VERSION 5.7 ;
BUSBITCHARS "[]" ;
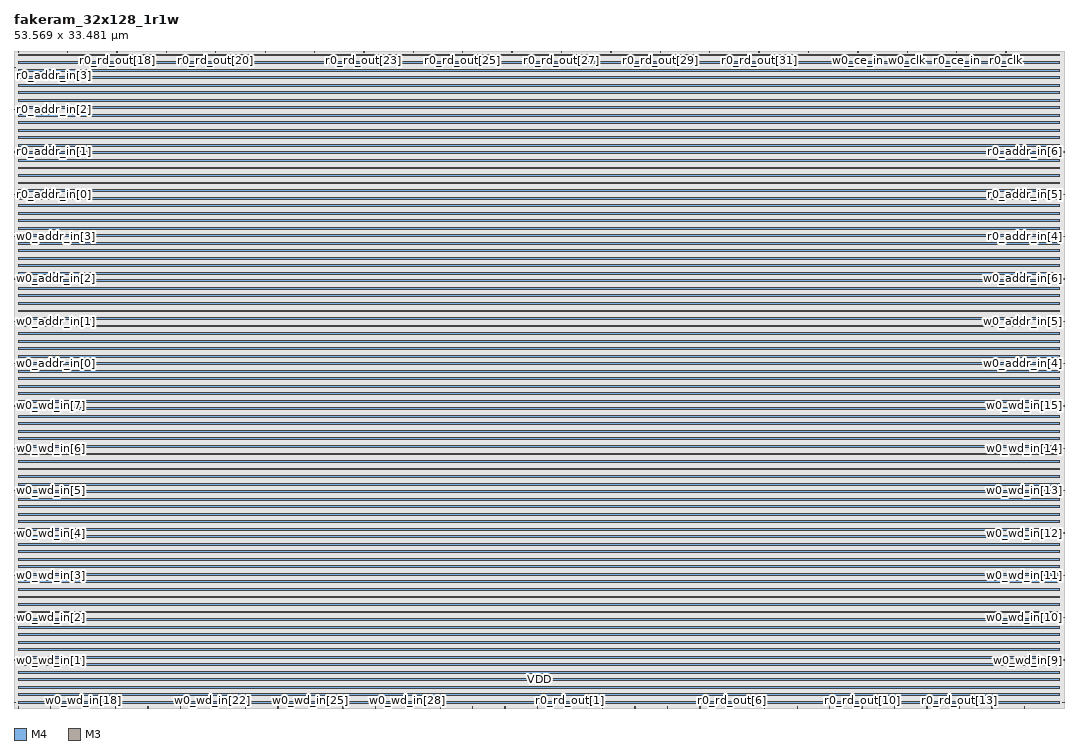
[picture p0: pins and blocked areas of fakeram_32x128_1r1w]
MACRO fakeram_32x128_1r1w
  FOREIGN fakeram_32x128_1r1w 0 0 ;
  SYMMETRY X Y R90 ;
  SIZE 53.569 BY 33.481 ;
  CLASS BLOCK ;
  PIN w0_wd_in[0]
    DIRECTION INPUT ;
    USE SIGNAL ;
    SHAPE ABUTMENT ;
    PORT
      LAYER M4 ;
      RECT 0.000 0.276 0.072 0.300 ;
    END
  END w0_wd_in[0]
  PIN w0_wd_in[1]
    DIRECTION INPUT ;
    USE SIGNAL ;
    SHAPE ABUTMENT ;
    PORT
      LAYER M4 ;
      RECT 0.000 2.436 0.072 2.460 ;
    END
  END w0_wd_in[1]
  PIN w0_wd_in[2]
    DIRECTION INPUT ;
    USE SIGNAL ;
    SHAPE ABUTMENT ;
    PORT
      LAYER M4 ;
      RECT 0.000 4.596 0.072 4.620 ;
    END
  END w0_wd_in[2]
  PIN w0_wd_in[3]
    DIRECTION INPUT ;
    USE SIGNAL ;
    SHAPE ABUTMENT ;
    PORT
      LAYER M4 ;
      RECT 0.000 6.756 0.072 6.780 ;
    END
  END w0_wd_in[3]
  PIN w0_wd_in[4]
    DIRECTION INPUT ;
    USE SIGNAL ;
    SHAPE ABUTMENT ;
    PORT
      LAYER M4 ;
      RECT 0.000 8.916 0.072 8.940 ;
    END
  END w0_wd_in[4]
  PIN w0_wd_in[5]
    DIRECTION INPUT ;
    USE SIGNAL ;
    SHAPE ABUTMENT ;
    PORT
      LAYER M4 ;
      RECT 0.000 11.076 0.072 11.100 ;
    END
  END w0_wd_in[5]
  PIN w0_wd_in[6]
    DIRECTION INPUT ;
    USE SIGNAL ;
    SHAPE ABUTMENT ;
    PORT
      LAYER M4 ;
      RECT 0.000 13.236 0.072 13.260 ;
    END
  END w0_wd_in[6]
  PIN w0_wd_in[7]
    DIRECTION INPUT ;
    USE SIGNAL ;
    SHAPE ABUTMENT ;
    PORT
      LAYER M4 ;
      RECT 0.000 15.396 0.072 15.420 ;
    END
  END w0_wd_in[7]
  PIN w0_wd_in[8]
    DIRECTION INPUT ;
    USE SIGNAL ;
    SHAPE ABUTMENT ;
    PORT
      LAYER M4 ;
      RECT 53.497 0.276 53.569 0.300 ;
    END
  END w0_wd_in[8]
  PIN w0_wd_in[9]
    DIRECTION INPUT ;
    USE SIGNAL ;
    SHAPE ABUTMENT ;
    PORT
      LAYER M4 ;
      RECT 53.497 2.436 53.569 2.460 ;
    END
  END w0_wd_in[9]
  PIN w0_wd_in[10]
    DIRECTION INPUT ;
    USE SIGNAL ;
    SHAPE ABUTMENT ;
    PORT
      LAYER M4 ;
      RECT 53.497 4.596 53.569 4.620 ;
    END
  END w0_wd_in[10]
  PIN w0_wd_in[11]
    DIRECTION INPUT ;
    USE SIGNAL ;
    SHAPE ABUTMENT ;
    PORT
      LAYER M4 ;
      RECT 53.497 6.756 53.569 6.780 ;
    END
  END w0_wd_in[11]
  PIN w0_wd_in[12]
    DIRECTION INPUT ;
    USE SIGNAL ;
    SHAPE ABUTMENT ;
    PORT
      LAYER M4 ;
      RECT 53.497 8.916 53.569 8.940 ;
    END
  END w0_wd_in[12]
  PIN w0_wd_in[13]
    DIRECTION INPUT ;
    USE SIGNAL ;
    SHAPE ABUTMENT ;
    PORT
      LAYER M4 ;
      RECT 53.497 11.076 53.569 11.100 ;
    END
  END w0_wd_in[13]
  PIN w0_wd_in[14]
    DIRECTION INPUT ;
    USE SIGNAL ;
    SHAPE ABUTMENT ;
    PORT
      LAYER M4 ;
      RECT 53.497 13.236 53.569 13.260 ;
    END
  END w0_wd_in[14]
  PIN w0_wd_in[15]
    DIRECTION INPUT ;
    USE SIGNAL ;
    SHAPE ABUTMENT ;
    PORT
      LAYER M4 ;
      RECT 53.497 15.396 53.569 15.420 ;
    END
  END w0_wd_in[15]
  PIN w0_wd_in[16]
    DIRECTION INPUT ;
    USE SIGNAL ;
    SHAPE ABUTMENT ;
    PORT
      LAYER M3 ;
      RECT 0.207 0.000 0.225 0.054 ;
    END
  END w0_wd_in[16]
  PIN w0_wd_in[17]
    DIRECTION INPUT ;
    USE SIGNAL ;
    SHAPE ABUTMENT ;
    PORT
      LAYER M3 ;
      RECT 1.863 0.000 1.881 0.054 ;
    END
  END w0_wd_in[17]
  PIN w0_wd_in[18]
    DIRECTION INPUT ;
    USE SIGNAL ;
    SHAPE ABUTMENT ;
    PORT
      LAYER M3 ;
      RECT 3.519 0.000 3.537 0.054 ;
    END
  END w0_wd_in[18]
  PIN w0_wd_in[19]
    DIRECTION INPUT ;
    USE SIGNAL ;
    SHAPE ABUTMENT ;
    PORT
      LAYER M3 ;
      RECT 5.175 0.000 5.193 0.054 ;
    END
  END w0_wd_in[19]
  PIN w0_wd_in[20]
    DIRECTION INPUT ;
    USE SIGNAL ;
    SHAPE ABUTMENT ;
    PORT
      LAYER M3 ;
      RECT 6.831 0.000 6.849 0.054 ;
    END
  END w0_wd_in[20]
  PIN w0_wd_in[21]
    DIRECTION INPUT ;
    USE SIGNAL ;
    SHAPE ABUTMENT ;
    PORT
      LAYER M3 ;
      RECT 8.487 0.000 8.505 0.054 ;
    END
  END w0_wd_in[21]
  PIN w0_wd_in[22]
    DIRECTION INPUT ;
    USE SIGNAL ;
    SHAPE ABUTMENT ;
    PORT
      LAYER M3 ;
      RECT 10.143 0.000 10.161 0.054 ;
    END
  END w0_wd_in[22]
  PIN w0_wd_in[23]
    DIRECTION INPUT ;
    USE SIGNAL ;
    SHAPE ABUTMENT ;
    PORT
      LAYER M3 ;
      RECT 11.799 0.000 11.817 0.054 ;
    END
  END w0_wd_in[23]
  PIN w0_wd_in[24]
    DIRECTION INPUT ;
    USE SIGNAL ;
    SHAPE ABUTMENT ;
    PORT
      LAYER M3 ;
      RECT 13.455 0.000 13.473 0.054 ;
    END
  END w0_wd_in[24]
  PIN w0_wd_in[25]
    DIRECTION INPUT ;
    USE SIGNAL ;
    SHAPE ABUTMENT ;
    PORT
      LAYER M3 ;
      RECT 15.111 0.000 15.129 0.054 ;
    END
  END w0_wd_in[25]
  PIN w0_wd_in[26]
    DIRECTION INPUT ;
    USE SIGNAL ;
    SHAPE ABUTMENT ;
    PORT
      LAYER M3 ;
      RECT 16.767 0.000 16.785 0.054 ;
    END
  END w0_wd_in[26]
  PIN w0_wd_in[27]
    DIRECTION INPUT ;
    USE SIGNAL ;
    SHAPE ABUTMENT ;
    PORT
      LAYER M3 ;
      RECT 18.423 0.000 18.441 0.054 ;
    END
  END w0_wd_in[27]
  PIN w0_wd_in[28]
    DIRECTION INPUT ;
    USE SIGNAL ;
    SHAPE ABUTMENT ;
    PORT
      LAYER M3 ;
      RECT 20.079 0.000 20.097 0.054 ;
    END
  END w0_wd_in[28]
  PIN w0_wd_in[29]
    DIRECTION INPUT ;
    USE SIGNAL ;
    SHAPE ABUTMENT ;
    PORT
      LAYER M3 ;
      RECT 21.735 0.000 21.753 0.054 ;
    END
  END w0_wd_in[29]
  PIN w0_wd_in[30]
    DIRECTION INPUT ;
    USE SIGNAL ;
    SHAPE ABUTMENT ;
    PORT
      LAYER M3 ;
      RECT 23.391 0.000 23.409 0.054 ;
    END
  END w0_wd_in[30]
  PIN w0_wd_in[31]
    DIRECTION INPUT ;
    USE SIGNAL ;
    SHAPE ABUTMENT ;
    PORT
      LAYER M3 ;
      RECT 25.047 0.000 25.065 0.054 ;
    END
  END w0_wd_in[31]
  PIN r0_rd_out[0]
    DIRECTION OUTPUT ;
    USE SIGNAL ;
    SHAPE ABUTMENT ;
    PORT
      LAYER M3 ;
      RECT 26.703 0.000 26.721 0.054 ;
    END
  END r0_rd_out[0]
  PIN r0_rd_out[1]
    DIRECTION OUTPUT ;
    USE SIGNAL ;
    SHAPE ABUTMENT ;
    PORT
      LAYER M3 ;
      RECT 28.359 0.000 28.377 0.054 ;
    END
  END r0_rd_out[1]
  PIN r0_rd_out[2]
    DIRECTION OUTPUT ;
    USE SIGNAL ;
    SHAPE ABUTMENT ;
    PORT
      LAYER M3 ;
      RECT 30.015 0.000 30.033 0.054 ;
    END
  END r0_rd_out[2]
  PIN r0_rd_out[3]
    DIRECTION OUTPUT ;
    USE SIGNAL ;
    SHAPE ABUTMENT ;
    PORT
      LAYER M3 ;
      RECT 31.671 0.000 31.689 0.054 ;
    END
  END r0_rd_out[3]
  PIN r0_rd_out[4]
    DIRECTION OUTPUT ;
    USE SIGNAL ;
    SHAPE ABUTMENT ;
    PORT
      LAYER M3 ;
      RECT 33.327 0.000 33.345 0.054 ;
    END
  END r0_rd_out[4]
  PIN r0_rd_out[5]
    DIRECTION OUTPUT ;
    USE SIGNAL ;
    SHAPE ABUTMENT ;
    PORT
      LAYER M3 ;
      RECT 34.983 0.000 35.001 0.054 ;
    END
  END r0_rd_out[5]
  PIN r0_rd_out[6]
    DIRECTION OUTPUT ;
    USE SIGNAL ;
    SHAPE ABUTMENT ;
    PORT
      LAYER M3 ;
      RECT 36.639 0.000 36.657 0.054 ;
    END
  END r0_rd_out[6]
  PIN r0_rd_out[7]
    DIRECTION OUTPUT ;
    USE SIGNAL ;
    SHAPE ABUTMENT ;
    PORT
      LAYER M3 ;
      RECT 38.295 0.000 38.313 0.054 ;
    END
  END r0_rd_out[7]
  PIN r0_rd_out[8]
    DIRECTION OUTPUT ;
    USE SIGNAL ;
    SHAPE ABUTMENT ;
    PORT
      LAYER M3 ;
      RECT 39.951 0.000 39.969 0.054 ;
    END
  END r0_rd_out[8]
  PIN r0_rd_out[9]
    DIRECTION OUTPUT ;
    USE SIGNAL ;
    SHAPE ABUTMENT ;
    PORT
      LAYER M3 ;
      RECT 41.607 0.000 41.625 0.054 ;
    END
  END r0_rd_out[9]
  PIN r0_rd_out[10]
    DIRECTION OUTPUT ;
    USE SIGNAL ;
    SHAPE ABUTMENT ;
    PORT
      LAYER M3 ;
      RECT 43.263 0.000 43.281 0.054 ;
    END
  END r0_rd_out[10]
  PIN r0_rd_out[11]
    DIRECTION OUTPUT ;
    USE SIGNAL ;
    SHAPE ABUTMENT ;
    PORT
      LAYER M3 ;
      RECT 44.919 0.000 44.937 0.054 ;
    END
  END r0_rd_out[11]
  PIN r0_rd_out[12]
    DIRECTION OUTPUT ;
    USE SIGNAL ;
    SHAPE ABUTMENT ;
    PORT
      LAYER M3 ;
      RECT 46.575 0.000 46.593 0.054 ;
    END
  END r0_rd_out[12]
  PIN r0_rd_out[13]
    DIRECTION OUTPUT ;
    USE SIGNAL ;
    SHAPE ABUTMENT ;
    PORT
      LAYER M3 ;
      RECT 48.231 0.000 48.249 0.054 ;
    END
  END r0_rd_out[13]
  PIN r0_rd_out[14]
    DIRECTION OUTPUT ;
    USE SIGNAL ;
    SHAPE ABUTMENT ;
    PORT
      LAYER M3 ;
      RECT 49.887 0.000 49.905 0.054 ;
    END
  END r0_rd_out[14]
  PIN r0_rd_out[15]
    DIRECTION OUTPUT ;
    USE SIGNAL ;
    SHAPE ABUTMENT ;
    PORT
      LAYER M3 ;
      RECT 51.543 0.000 51.561 0.054 ;
    END
  END r0_rd_out[15]
  PIN r0_rd_out[16]
    DIRECTION OUTPUT ;
    USE SIGNAL ;
    SHAPE ABUTMENT ;
    PORT
      LAYER M3 ;
      RECT 0.207 33.427 0.225 33.481 ;
    END
  END r0_rd_out[16]
  PIN r0_rd_out[17]
    DIRECTION OUTPUT ;
    USE SIGNAL ;
    SHAPE ABUTMENT ;
    PORT
      LAYER M3 ;
      RECT 2.727 33.427 2.745 33.481 ;
    END
  END r0_rd_out[17]
  PIN r0_rd_out[18]
    DIRECTION OUTPUT ;
    USE SIGNAL ;
    SHAPE ABUTMENT ;
    PORT
      LAYER M3 ;
      RECT 5.247 33.427 5.265 33.481 ;
    END
  END r0_rd_out[18]
  PIN r0_rd_out[19]
    DIRECTION OUTPUT ;
    USE SIGNAL ;
    SHAPE ABUTMENT ;
    PORT
      LAYER M3 ;
      RECT 7.767 33.427 7.785 33.481 ;
    END
  END r0_rd_out[19]
  PIN r0_rd_out[20]
    DIRECTION OUTPUT ;
    USE SIGNAL ;
    SHAPE ABUTMENT ;
    PORT
      LAYER M3 ;
      RECT 10.287 33.427 10.305 33.481 ;
    END
  END r0_rd_out[20]
  PIN r0_rd_out[21]
    DIRECTION OUTPUT ;
    USE SIGNAL ;
    SHAPE ABUTMENT ;
    PORT
      LAYER M3 ;
      RECT 12.807 33.427 12.825 33.481 ;
    END
  END r0_rd_out[21]
  PIN r0_rd_out[22]
    DIRECTION OUTPUT ;
    USE SIGNAL ;
    SHAPE ABUTMENT ;
    PORT
      LAYER M3 ;
      RECT 15.327 33.427 15.345 33.481 ;
    END
  END r0_rd_out[22]
  PIN r0_rd_out[23]
    DIRECTION OUTPUT ;
    USE SIGNAL ;
    SHAPE ABUTMENT ;
    PORT
      LAYER M3 ;
      RECT 17.847 33.427 17.865 33.481 ;
    END
  END r0_rd_out[23]
  PIN r0_rd_out[24]
    DIRECTION OUTPUT ;
    USE SIGNAL ;
    SHAPE ABUTMENT ;
    PORT
      LAYER M3 ;
      RECT 20.367 33.427 20.385 33.481 ;
    END
  END r0_rd_out[24]
  PIN r0_rd_out[25]
    DIRECTION OUTPUT ;
    USE SIGNAL ;
    SHAPE ABUTMENT ;
    PORT
      LAYER M3 ;
      RECT 22.887 33.427 22.905 33.481 ;
    END
  END r0_rd_out[25]
  PIN r0_rd_out[26]
    DIRECTION OUTPUT ;
    USE SIGNAL ;
    SHAPE ABUTMENT ;
    PORT
      LAYER M3 ;
      RECT 25.407 33.427 25.425 33.481 ;
    END
  END r0_rd_out[26]
  PIN r0_rd_out[27]
    DIRECTION OUTPUT ;
    USE SIGNAL ;
    SHAPE ABUTMENT ;
    PORT
      LAYER M3 ;
      RECT 27.927 33.427 27.945 33.481 ;
    END
  END r0_rd_out[27]
  PIN r0_rd_out[28]
    DIRECTION OUTPUT ;
    USE SIGNAL ;
    SHAPE ABUTMENT ;
    PORT
      LAYER M3 ;
      RECT 30.447 33.427 30.465 33.481 ;
    END
  END r0_rd_out[28]
  PIN r0_rd_out[29]
    DIRECTION OUTPUT ;
    USE SIGNAL ;
    SHAPE ABUTMENT ;
    PORT
      LAYER M3 ;
      RECT 32.967 33.427 32.985 33.481 ;
    END
  END r0_rd_out[29]
  PIN r0_rd_out[30]
    DIRECTION OUTPUT ;
    USE SIGNAL ;
    SHAPE ABUTMENT ;
    PORT
      LAYER M3 ;
      RECT 35.487 33.427 35.505 33.481 ;
    END
  END r0_rd_out[30]
  PIN r0_rd_out[31]
    DIRECTION OUTPUT ;
    USE SIGNAL ;
    SHAPE ABUTMENT ;
    PORT
      LAYER M3 ;
      RECT 38.007 33.427 38.025 33.481 ;
    END
  END r0_rd_out[31]
  PIN w0_addr_in[0]
    DIRECTION INPUT ;
    USE SIGNAL ;
    SHAPE ABUTMENT ;
    PORT
      LAYER M4 ;
      RECT 0.000 17.556 0.072 17.580 ;
    END
  END w0_addr_in[0]
  PIN w0_addr_in[1]
    DIRECTION INPUT ;
    USE SIGNAL ;
    SHAPE ABUTMENT ;
    PORT
      LAYER M4 ;
      RECT 0.000 19.716 0.072 19.740 ;
    END
  END w0_addr_in[1]
  PIN w0_addr_in[2]
    DIRECTION INPUT ;
    USE SIGNAL ;
    SHAPE ABUTMENT ;
    PORT
      LAYER M4 ;
      RECT 0.000 21.876 0.072 21.900 ;
    END
  END w0_addr_in[2]
  PIN w0_addr_in[3]
    DIRECTION INPUT ;
    USE SIGNAL ;
    SHAPE ABUTMENT ;
    PORT
      LAYER M4 ;
      RECT 0.000 24.036 0.072 24.060 ;
    END
  END w0_addr_in[3]
  PIN w0_addr_in[4]
    DIRECTION INPUT ;
    USE SIGNAL ;
    SHAPE ABUTMENT ;
    PORT
      LAYER M4 ;
      RECT 53.497 17.556 53.569 17.580 ;
    END
  END w0_addr_in[4]
  PIN w0_addr_in[5]
    DIRECTION INPUT ;
    USE SIGNAL ;
    SHAPE ABUTMENT ;
    PORT
      LAYER M4 ;
      RECT 53.497 19.716 53.569 19.740 ;
    END
  END w0_addr_in[5]
  PIN w0_addr_in[6]
    DIRECTION INPUT ;
    USE SIGNAL ;
    SHAPE ABUTMENT ;
    PORT
      LAYER M4 ;
      RECT 53.497 21.876 53.569 21.900 ;
    END
  END w0_addr_in[6]
  PIN r0_addr_in[0]
    DIRECTION INPUT ;
    USE SIGNAL ;
    SHAPE ABUTMENT ;
    PORT
      LAYER M4 ;
      RECT 0.000 26.196 0.072 26.220 ;
    END
  END r0_addr_in[0]
  PIN r0_addr_in[1]
    DIRECTION INPUT ;
    USE SIGNAL ;
    SHAPE ABUTMENT ;
    PORT
      LAYER M4 ;
      RECT 0.000 28.356 0.072 28.380 ;
    END
  END r0_addr_in[1]
  PIN r0_addr_in[2]
    DIRECTION INPUT ;
    USE SIGNAL ;
    SHAPE ABUTMENT ;
    PORT
      LAYER M4 ;
      RECT 0.000 30.516 0.072 30.540 ;
    END
  END r0_addr_in[2]
  PIN r0_addr_in[3]
    DIRECTION INPUT ;
    USE SIGNAL ;
    SHAPE ABUTMENT ;
    PORT
      LAYER M4 ;
      RECT 0.000 32.676 0.072 32.700 ;
    END
  END r0_addr_in[3]
  PIN r0_addr_in[4]
    DIRECTION INPUT ;
    USE SIGNAL ;
    SHAPE ABUTMENT ;
    PORT
      LAYER M4 ;
      RECT 53.497 24.036 53.569 24.060 ;
    END
  END r0_addr_in[4]
  PIN r0_addr_in[5]
    DIRECTION INPUT ;
    USE SIGNAL ;
    SHAPE ABUTMENT ;
    PORT
      LAYER M4 ;
      RECT 53.497 26.196 53.569 26.220 ;
    END
  END r0_addr_in[5]
  PIN r0_addr_in[6]
    DIRECTION INPUT ;
    USE SIGNAL ;
    SHAPE ABUTMENT ;
    PORT
      LAYER M4 ;
      RECT 53.497 28.356 53.569 28.380 ;
    END
  END r0_addr_in[6]
  PIN w0_we_in
    DIRECTION INPUT ;
    USE SIGNAL ;
    SHAPE ABUTMENT ;
    PORT
      LAYER M3 ;
      RECT 40.527 33.427 40.545 33.481 ;
    END
  END w0_we_in
  PIN w0_ce_in
    DIRECTION INPUT ;
    USE SIGNAL ;
    SHAPE ABUTMENT ;
    PORT
      LAYER M3 ;
      RECT 43.047 33.427 43.065 33.481 ;
    END
  END w0_ce_in
  PIN w0_clk
    DIRECTION INPUT ;
    USE SIGNAL ;
    SHAPE ABUTMENT ;
    PORT
      LAYER M3 ;
      RECT 45.567 33.427 45.585 33.481 ;
    END
  END w0_clk
  PIN r0_ce_in
    DIRECTION INPUT ;
    USE SIGNAL ;
    SHAPE ABUTMENT ;
    PORT
      LAYER M3 ;
      RECT 48.087 33.427 48.105 33.481 ;
    END
  END r0_ce_in
  PIN r0_clk
    DIRECTION INPUT ;
    USE SIGNAL ;
    SHAPE ABUTMENT ;
    PORT
      LAYER M3 ;
      RECT 50.607 33.427 50.625 33.481 ;
    END
  END r0_clk
  PIN VSS
    DIRECTION INOUT ;
    USE GROUND ;
    PORT
      LAYER M4 ;
      RECT 0.216 0.240 53.353 0.336 ;
      RECT 0.216 1.008 53.353 1.104 ;
      RECT 0.216 1.776 53.353 1.872 ;
      RECT 0.216 2.544 53.353 2.640 ;
      RECT 0.216 3.312 53.353 3.408 ;
      RECT 0.216 4.080 53.353 4.176 ;
      RECT 0.216 4.848 53.353 4.944 ;
      RECT 0.216 5.616 53.353 5.712 ;
      RECT 0.216 6.384 53.353 6.480 ;
      RECT 0.216 7.152 53.353 7.248 ;
      RECT 0.216 7.920 53.353 8.016 ;
      RECT 0.216 8.688 53.353 8.784 ;
      RECT 0.216 9.456 53.353 9.552 ;
      RECT 0.216 10.224 53.353 10.320 ;
      RECT 0.216 10.992 53.353 11.088 ;
      RECT 0.216 11.760 53.353 11.856 ;
      RECT 0.216 12.528 53.353 12.624 ;
      RECT 0.216 13.296 53.353 13.392 ;
      RECT 0.216 14.064 53.353 14.160 ;
      RECT 0.216 14.832 53.353 14.928 ;
      RECT 0.216 15.600 53.353 15.696 ;
      RECT 0.216 16.368 53.353 16.464 ;
      RECT 0.216 17.136 53.353 17.232 ;
      RECT 0.216 17.904 53.353 18.000 ;
      RECT 0.216 18.672 53.353 18.768 ;
      RECT 0.216 19.440 53.353 19.536 ;
      RECT 0.216 20.208 53.353 20.304 ;
      RECT 0.216 20.976 53.353 21.072 ;
      RECT 0.216 21.744 53.353 21.840 ;
      RECT 0.216 22.512 53.353 22.608 ;
      RECT 0.216 23.280 53.353 23.376 ;
      RECT 0.216 24.048 53.353 24.144 ;
      RECT 0.216 24.816 53.353 24.912 ;
      RECT 0.216 25.584 53.353 25.680 ;
      RECT 0.216 26.352 53.353 26.448 ;
      RECT 0.216 27.120 53.353 27.216 ;
      RECT 0.216 27.888 53.353 27.984 ;
      RECT 0.216 28.656 53.353 28.752 ;
      RECT 0.216 29.424 53.353 29.520 ;
      RECT 0.216 30.192 53.353 30.288 ;
      RECT 0.216 30.960 53.353 31.056 ;
      RECT 0.216 31.728 53.353 31.824 ;
      RECT 0.216 32.496 53.353 32.592 ;
      RECT 0.216 33.264 53.353 33.360 ;
    END
  END VSS
  PIN VDD
    DIRECTION INOUT ;
    USE POWER ;
    PORT
      LAYER M4 ;
      RECT 0.216 0.624 53.353 0.720 ;
      RECT 0.216 1.392 53.353 1.488 ;
      RECT 0.216 2.160 53.353 2.256 ;
      RECT 0.216 2.928 53.353 3.024 ;
      RECT 0.216 3.696 53.353 3.792 ;
      RECT 0.216 4.464 53.353 4.560 ;
      RECT 0.216 5.232 53.353 5.328 ;
      RECT 0.216 6.000 53.353 6.096 ;
      RECT 0.216 6.768 53.353 6.864 ;
      RECT 0.216 7.536 53.353 7.632 ;
      RECT 0.216 8.304 53.353 8.400 ;
      RECT 0.216 9.072 53.353 9.168 ;
      RECT 0.216 9.840 53.353 9.936 ;
      RECT 0.216 10.608 53.353 10.704 ;
      RECT 0.216 11.376 53.353 11.472 ;
      RECT 0.216 12.144 53.353 12.240 ;
      RECT 0.216 12.912 53.353 13.008 ;
      RECT 0.216 13.680 53.353 13.776 ;
      RECT 0.216 14.448 53.353 14.544 ;
      RECT 0.216 15.216 53.353 15.312 ;
      RECT 0.216 15.984 53.353 16.080 ;
      RECT 0.216 16.752 53.353 16.848 ;
      RECT 0.216 17.520 53.353 17.616 ;
      RECT 0.216 18.288 53.353 18.384 ;
      RECT 0.216 19.056 53.353 19.152 ;
      RECT 0.216 19.824 53.353 19.920 ;
      RECT 0.216 20.592 53.353 20.688 ;
      RECT 0.216 21.360 53.353 21.456 ;
      RECT 0.216 22.128 53.353 22.224 ;
      RECT 0.216 22.896 53.353 22.992 ;
      RECT 0.216 23.664 53.353 23.760 ;
      RECT 0.216 24.432 53.353 24.528 ;
      RECT 0.216 25.200 53.353 25.296 ;
      RECT 0.216 25.968 53.353 26.064 ;
      RECT 0.216 26.736 53.353 26.832 ;
      RECT 0.216 27.504 53.353 27.600 ;
      RECT 0.216 28.272 53.353 28.368 ;
      RECT 0.216 29.040 53.353 29.136 ;
      RECT 0.216 29.808 53.353 29.904 ;
      RECT 0.216 30.576 53.353 30.672 ;
      RECT 0.216 31.344 53.353 31.440 ;
      RECT 0.216 32.112 53.353 32.208 ;
      RECT 0.216 32.880 53.353 32.976 ;
    END
  END VDD
  OBS
    LAYER M1 ;
    RECT 0 0 53.569 33.481 ;
    LAYER M2 ;
    RECT 0 0 53.569 33.481 ;
    LAYER M3 ;
    RECT 0 0 53.569 33.481 ;
    LAYER M4 ;
    RECT 0 0 53.569 33.481 ;
  END
END fakeram_32x128_1r1w

END LIBRARY
